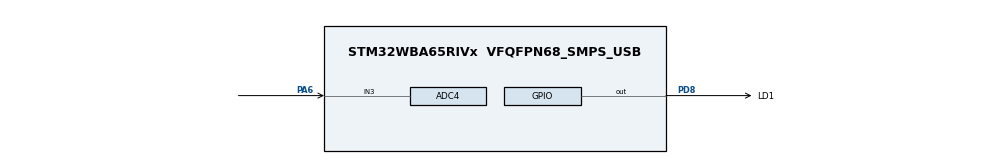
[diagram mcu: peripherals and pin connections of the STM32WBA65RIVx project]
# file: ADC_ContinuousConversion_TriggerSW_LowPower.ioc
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ADC4.Channel-0\#ChannelRegularConversion=ADC_CHANNEL_3
ADC4.ClockPrescaler=ADC_CLOCK_ASYNC_DIV4
ADC4.ContinuousConvMode=ENABLE
ADC4.LowPowerAutoPowerOff=ENABLE
ADC4.LowPowerAutoWait=ENABLE
ADC4.NbrOfConversionFlag=1
ADC4.Overrun=ADC_OVR_DATA_OVERWRITTEN
ADC4.Rank-0\#ChannelRegularConversion=1
ADC4.SamplingTime-0\#ChannelRegularConversion=ADC_SAMPLINGTIME_COMMON_1
ADC4.SamplingTimeCommon1=ADC_SAMPLETIME_79CYCLES_5
ADC4.SamplingTimeCommon2=ADC_SAMPLETIME_79CYCLES_5
ADC4.SelectedChannel=ADC_CHANNEL_3
CORTEX_M33_NS.userName=CORTEX_M33
Mcu.Family=STM32WBA
Mcu.Name=STM32WBA65RIVx
Mcu.Package=VFQFPN68_SMPS_USB
NVIC.PriorityGroup=NVIC_PRIORITYGROUP_4
OSC_IN.Mode=HSE-External-Oscillator
OSC_IN.PinAttribute=CortexM33
OSC_IN.Signal=RCC_OSC_IN
OSC_OUT.Mode=HSE-External-Oscillator
OSC_OUT.PinAttribute=CortexM33
OSC_OUT.Signal=RCC_OSC_OUT
PA6.Mode=IN3
PA6.PinAttribute=CortexM33
PA6.Signal=ADC4_IN3
PD8.GPIO_Label=LD1
PD8.PinAttribute=Free
PD8.Signal=GPIO_Output
ProjectManager.HeapSize=0x200
ProjectManager.StackSize=0x400
ProjectManager.TargetToolchain=EWARM V9.20
RCC.ADCFreq_Value=100000000
RCC.AHB5CLKDivider=DIV4
RCC.AHBFreq_Value=100000000
RCC.APB1Freq_Value=100000000
RCC.APB1TimFreq_Value=100000000
RCC.APB2Freq_Value=100000000
RCC.APB2TimFreq_Value=100000000
RCC.CortexFreq_Value=12500000
RCC.HCLKFreq_Value=100000000
RCC.HSE_VALUE=32000000
RCC.HSI_VALUE=16000000
RCC.LSE_VALUE=32768
RCC.LSI1_VALUE=32000
RCC.LSI2_VALUE=32000
RCC.PLLFRACN=4096
RCC.PLLM=2
RCC.PLLN=12
RCC.PLLSourceVirtual=RCC_PLLSOURCE_HSE
RCC.SYSCLKFreq_VALUE=100000000
RCC.SYSCLKSourceVirtual=RCC_SYSCLKSOURCE_PLLCLK
RCC.VCOOutputFreq_Value=200000000
VP_CORTEX_M33_NS_VS_Hclk.Mode=Hclk_Mode
VP_ICACHE_VS_ICACHE.Mode=DirectMappedCache
VP_PWR_VS_SECSignals.Mode=Security/Privilege
board=custom

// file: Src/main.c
/* USER CODE BEGIN Header */
/**
  ******************************************************************************
  * @file    Examples/ADC/ADC_ContinuousConversion_TriggerSW_LowPower/Src/main.c
  * @author  MCD Application Team
  * @brief   Use ADC to convert a single channel with ADC low power features
  *          auto wait and auto power-off: ADC conversions occurrences are
  *          limited to the minimum necessary to reduce power consumption
  *          and ADC is set automatically in mode disable during idle phase.

  *          These features are intended to be used by applications needing ADC
  *          conversions at few occurrences and without latency constraints.
  *          ADC low power features are used most commonly with programming
  *          model: polling.
  *          This example is based on the STM32WBAxx ADC LL API;
  *          Peripheral initialization done using LL unitary services functions.
  ******************************************************************************
  * @attention
  *
  * <h2><center>&copy; Copyright (c) 2024 STMicroelectronics.
  * All rights reserved.</center></h2>
  *
  * This software component is licensed by ST under BSD 3-Clause license,
  * the "License"; You may not use this file except in compliance with the
  * License. You may obtain a copy of the License at:
  *                        opensource.org/licenses/BSD-3-Clause
  *
  ******************************************************************************
  */
/* USER CODE END Header */
#include "main.h"

/* USER CODE BEGIN PD */

/* Definitions of environment analog values */
  /* Value of analog reference voltage (Vref+), connected to analog voltage   */
  /* supply Vdda (unit: mV).                                                  */
  #define VDDA_APPLI                       (3300UL)

/* Definitions of data related to this example */
  /* Init variable out of expected ADC conversion data range */
  #define VAR_CONVERTED_DATA_INIT_VALUE    (__LL_ADC_DIGITAL_SCALE(LL_ADC_RESOLUTION_12B) + 1)

/* USER CODE END PD */

ADC_HandleTypeDef hadc4;

/* USER CODE BEGIN PV */

/* Variables for ADC conversion data */
__IO uint16_t uhADCxConvertedData = VAR_CONVERTED_DATA_INIT_VALUE; /* ADC group regular conversion data */

/* Variables for ADC conversion data computation to physical values */
uint16_t uhADCxConvertedData_Voltage_mVolt = 0;  /* Value of voltage calculated from ADC conversion data (unit: mV) */

/* USER CODE END PV */

void SystemClock_Config(void);
static void MX_GPIO_Init(void);
static void MX_ICACHE_Init(void);
static void MX_ADC4_Init(void);

int main(void)
{

  /* MCU Configuration--------------------------------------------------------*/

  /* Reset of all peripherals, Initializes the Flash interface and the Systick. */
  HAL_Init();

  /* Configure the system clock */
  SystemClock_Config();

  /* Initialize all configured peripherals */
  MX_GPIO_Init();
  MX_ICACHE_Init();
  MX_ADC4_Init();
  /* USER CODE BEGIN 2 */

  /* Initialize LED on board */
  BSP_LED_Init(LD1);

  /* Perform ADC calibration */
  if (HAL_ADCEx_Calibration_Start(&hadc4) != HAL_OK)
  {
    /* Calibration Error */
    Error_Handler();
  }

    /* Start ADC group regular conversion */
    if (HAL_ADC_Start(&hadc4) != HAL_OK)
    {
      /* ADC conversion start error */
      Error_Handler();
    }

    /* Wait for ADC conversion completed */
    if (HAL_ADC_PollForConversion(&hadc4, 10) != HAL_OK)
    {
      /* End Of Conversion flag not set on time */
      Error_Handler();
    }

  /* USER CODE END 2 */

  /* Infinite loop */
  /* USER CODE BEGIN WHILE */
  while (1)
  {
    /* Note: At this step, ADC is performing ADC conversions automatically,   */
    /*       indefinitely (ADC continuous mode enabled in this example),      */
    /*       but with conversions managed by ADC mode low-power:              */
    /*       After the first trigger (software start in this example),        */
    /*       following conversions are not launched successively              */
    /*       automatically: the ADC performs 1 conversion and remains idle    */
    /*       until conversion data has been processed by user software        */
    /*       (action of retrieve conversion value from ADC data register)     */
    /*       On this STM32 series, on which ADC low power feature             */
    /*       auto power-off is available, ADC is set automatically            */
    /*       in mode disable during idle phase. Then, when ADC conversion     */
    /*       is requested, ADC is set automatically in mode enable.           */

    /* Retrieve ADC conversion data */
    /* Note: As ADC mode low power auto wait is enabled, this action          */
    /*       performs:                                                        */
    /*       - ADC conversion data read                                       */
    /*         Caution: the data read corresponds to the previous ADC         */
    /*         conversion start, independently of delay during which ADC      */
    /*         was idle (low power auto wait). Therefore, ADC conversion      */
    /*         data may be outdated: does not correspond to the current       */
    /*         voltage level on the selected ADC channel.                     */
    /*       - Trig of a new ADC conversion start                             */
    /* Note: In ADC mode low power auto wait, the action triggering a         */
    /*       ADC conversion start is a clear of flag "end of conversion."     */
    /*       - For ADC group regular, ADC conversion data read performs       */
    /*         automatically a clear of flag ADC group regular                */
    /*         end of unitary conversion.                                     */
    /*         Therefore, usage of function "LL_ADC_ClearFlag_EOC()" is not   */
    /*         necessary.                                                     */
    /*       - For ADC group injected (for devices with this features),       */
    /*         data read does not performs a clear of flag ADC group injected */
    /*         end of sequence conversions.                                   */
    /*         Therefore, usage of function "LL_ADC_ClearFlag_JEOS()" is      */
    /*         mandatory.                                                     */

    /* Retrieve ADC conversion data */
    uhADCxConvertedData = HAL_ADC_GetValue(&hadc4);

    /* Note: As ADC mode low power auto wait is enabled, after the conversion */
    /*       on going, ADC will remain idle from this step.                   */

    /* Computation of ADC conversions raw data to physical values             */
    /* using helper macro.                                                    */
    uhADCxConvertedData_Voltage_mVolt = __LL_ADC_CALC_DATA_TO_VOLTAGE(VDDA_APPLI, uhADCxConvertedData, LL_ADC_RESOLUTION_12B);

    /* Toggle LED at each ADC conversion data retrieved */
    BSP_LED_On(LD1);
    HAL_Delay(LED_BLINK_SLOW);
    BSP_LED_Off(LD1);
    HAL_Delay(LED_BLINK_SLOW);

    /* Note: ADC group regular conversions data are stored into array         */
    /*       "uhADCxConvertedData"                                            */
    /*       (for debug: see variable content into watch window).             */

    /* Note: ADC conversion data are computed to physical values              */
    /*       into array "uhADCxConvertedData_Voltage_mVolt" using             */
    /*       ADC LL driver helper macro "__LL_ADC_CALC_DATA_TO_VOLTAGE()"     */
    /*       (for debug: see variable content with debugger)                  */

    /* USER CODE END WHILE */

  }
}

void SystemClock_Config(void)
{
  RCC_OscInitTypeDef RCC_OscInitStruct = {0};
  RCC_ClkInitTypeDef RCC_ClkInitStruct = {0};

  /** Supply configuration update enable
  */
  HAL_PWREx_ConfigSupply(PWR_LDO_SUPPLY);

  /** Configure the main internal regulator output voltage
  */
  if (HAL_PWREx_ControlVoltageScaling(PWR_REGULATOR_VOLTAGE_SCALE1) != HAL_OK)
  {
    Error_Handler();
  }

  /** Initializes the CPU, AHB and APB busses clocks
  */
  RCC_OscInitStruct.OscillatorType = RCC_OSCILLATORTYPE_HSE;
  RCC_OscInitStruct.HSEState = RCC_HSE_ON;
  RCC_OscInitStruct.HSEDiv = RCC_HSE_DIV1;
  RCC_OscInitStruct.PLL1.PLLState = RCC_PLL_ON;
  RCC_OscInitStruct.PLL1.PLLSource = RCC_PLLSOURCE_HSE;
  RCC_OscInitStruct.PLL1.PLLM = 2;
  RCC_OscInitStruct.PLL1.PLLN = 12;
  RCC_OscInitStruct.PLL1.PLLP = 2;
  RCC_OscInitStruct.PLL1.PLLQ = 2;
  RCC_OscInitStruct.PLL1.PLLR = 2;
  RCC_OscInitStruct.PLL1.PLLFractional = 4096;
  if (HAL_RCC_OscConfig(&RCC_OscInitStruct) != HAL_OK)
  {
    Error_Handler();
  }

  /** Initializes the CPU, AHB and APB busses clocks
  */
  RCC_ClkInitStruct.ClockType = RCC_CLOCKTYPE_HCLK|RCC_CLOCKTYPE_SYSCLK
                              |RCC_CLOCKTYPE_PCLK1|RCC_CLOCKTYPE_PCLK2
                              |RCC_CLOCKTYPE_PCLK7|RCC_CLOCKTYPE_HCLK5;
  RCC_ClkInitStruct.SYSCLKSource = RCC_SYSCLKSOURCE_PLLCLK;
  RCC_ClkInitStruct.AHBCLKDivider = RCC_SYSCLK_DIV1;
  RCC_ClkInitStruct.APB1CLKDivider = RCC_HCLK_DIV1;
  RCC_ClkInitStruct.APB2CLKDivider = RCC_HCLK_DIV1;
  RCC_ClkInitStruct.APB7CLKDivider = RCC_HCLK_DIV1;
  RCC_ClkInitStruct.AHB5_PLL1_CLKDivider = RCC_SYSCLK_PLL1_DIV4;
  RCC_ClkInitStruct.AHB5_HSEHSI_CLKDivider = RCC_SYSCLK_HSEHSI_DIV1;

  if (HAL_RCC_ClockConfig(&RCC_ClkInitStruct, FLASH_LATENCY_3) != HAL_OK)
  {
    Error_Handler();
  }
}

static void MX_ADC4_Init(void)
{

  ADC_ChannelConfTypeDef sConfig = {0};

  /** Common config
  */
  hadc4.Instance = ADC4;
  hadc4.Init.ClockPrescaler = ADC_CLOCK_ASYNC_DIV4;
  hadc4.Init.Resolution = ADC_RESOLUTION_12B;
  hadc4.Init.DataAlign = ADC_DATAALIGN_RIGHT;
  hadc4.Init.ScanConvMode = ADC_SCAN_DISABLE;
  hadc4.Init.EOCSelection = ADC_EOC_SINGLE_CONV;
  hadc4.Init.LowPowerAutoPowerOff = ENABLE;
  hadc4.Init.LowPowerAutonomousDPD = ADC_LP_AUTONOMOUS_DPD_DISABLE;
  hadc4.Init.LowPowerAutoWait = ENABLE;
  hadc4.Init.ContinuousConvMode = ENABLE;
  hadc4.Init.NbrOfConversion = 1;
  hadc4.Init.ExternalTrigConv = ADC_SOFTWARE_START;
  hadc4.Init.ExternalTrigConvEdge = ADC_EXTERNALTRIGCONVEDGE_NONE;
  hadc4.Init.DMAContinuousRequests = DISABLE;
  hadc4.Init.TriggerFrequencyMode = ADC_TRIGGER_FREQ_LOW;
  hadc4.Init.Overrun = ADC_OVR_DATA_OVERWRITTEN;
  hadc4.Init.SamplingTimeCommon1 = ADC_SAMPLETIME_79CYCLES_5;
  hadc4.Init.SamplingTimeCommon2 = ADC_SAMPLETIME_79CYCLES_5;
  hadc4.Init.OversamplingMode = DISABLE;
  if (HAL_ADC_Init(&hadc4) != HAL_OK)
  {
    Error_Handler();
  }

  /** Configure Regular Channel
  */
  sConfig.Channel = ADC_CHANNEL_3;
  sConfig.Rank = ADC_REGULAR_RANK_1;
  sConfig.SamplingTime = ADC_SAMPLINGTIME_COMMON_1;
  if (HAL_ADC_ConfigChannel(&hadc4, &sConfig) != HAL_OK)
  {
    Error_Handler();
  }

}

static void MX_ICACHE_Init(void)
{

  /** Enable instruction cache in 1-way (direct mapped cache)
  */
  if (HAL_ICACHE_ConfigAssociativityMode(ICACHE_1WAY) != HAL_OK)
  {
    Error_Handler();
  }
  if (HAL_ICACHE_Enable() != HAL_OK)
  {
    Error_Handler();
  }

}

static void MX_GPIO_Init(void)
{
  GPIO_InitTypeDef GPIO_InitStruct = {0};

  /* GPIO Ports Clock Enable */
  __HAL_RCC_GPIOA_CLK_ENABLE();
  __HAL_RCC_GPIOD_CLK_ENABLE();

  /*Configure GPIO pin Output Level */
  HAL_GPIO_WritePin(LD1_GPIO_Port, LD1_Pin, GPIO_PIN_RESET);

  /*Configure GPIO pin : LD1_Pin */
  GPIO_InitStruct.Pin = LD1_Pin;
  GPIO_InitStruct.Mode = GPIO_MODE_OUTPUT_PP;
  GPIO_InitStruct.Pull = GPIO_NOPULL;
  GPIO_InitStruct.Speed = GPIO_SPEED_FREQ_LOW;
  HAL_GPIO_Init(LD1_GPIO_Port, &GPIO_InitStruct);

}

void Error_Handler(void)
{
  /* USER CODE BEGIN Error_Handler_Debug */
  /* User can add his own implementation to report the HAL error return state */

  /* Turn on LED and remain in infinite loop */
  while (1)
  {
    BSP_LED_On(LD1);
  }
  /* USER CODE END Error_Handler_Debug */
}
